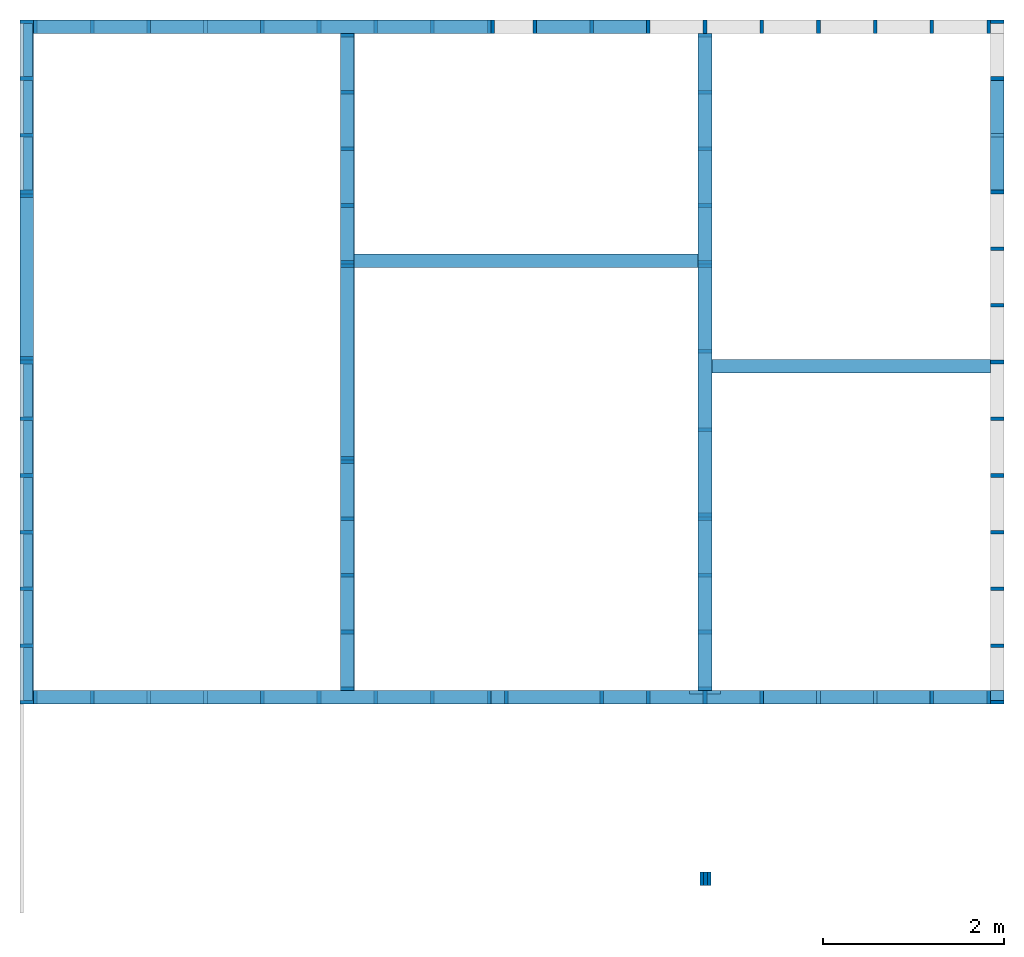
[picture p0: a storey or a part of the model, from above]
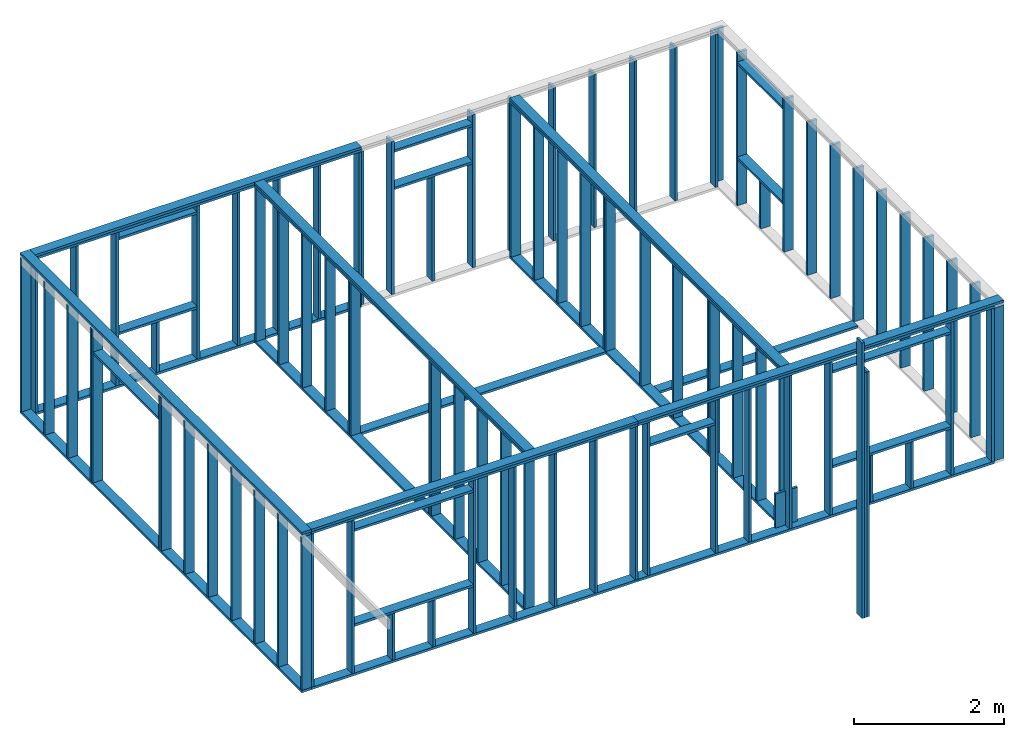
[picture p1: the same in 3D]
Properties of the parts of a building model (IFC4)

# File
Description: ViewDefinition [Renga View]
File name: Прокт каркасного дома.ifc
Time: 2023-05-16T19:59:36
Author: Fujitsu
Written by: IfcPlusPlus
Made in: Renga 5.11.49403.0

# IfcBuildingStorey (5)
Name | Elevation (mm) | Reference
Базовый уровень | 0 | Базовый уровень
Фасады | 0 | Фасады
Ниже 0.00 | 0 | Ниже 0.00
Кровля | 2620 | Кровля
Земля | -700 | Земля

# IfcBeam: Брус 40х40 (6)
In: Кровля
Type - PredefinedType: BEAM
Material: Древесина зел
Qto_BeamBaseQuantities - CrossSectionArea: 0.0016 m2
Name | Roll (deg) | Length (mm) | NetVolume (m3) | NetWeight (kg) | OuterSurfaceArea (m2)
4 x Балка - Брус 40х40 | 72.4 | 1500 | 0.00216 | 1.296 | 0.224
2 x Балка - Брус 40х40 | 0 | 4500 | 0.0072 | 4.32 | 0.72

# IfcBeam: Доска 25х100 (12)
In: Фасады
Type - PredefinedType: BEAM
Material: Древесина белая крашенная
Qto_BeamBaseQuantities - CrossSectionArea: 0.0025 m2
Name | Roll (deg) | Length (mm) | NetVolume (m3) | NetWeight (kg) | OuterSurfaceArea (m2)
Балка - Доска 25х100 | 0 | 2980.77 | 0.00730193 | 4.38116 | 0.742693
Балка - Доска 25х100 | 90 | 1841.45 | 0.00460362 | 2.76217 | 0.460362
Балка - Доска 25х100 | 90 | 2783.76 | 0.00695941 | 4.17565 | 0.695941
Балка - Доска 25х100 | 0 | 2980.77 | 0.00735818 | 4.41491 | 0.738943
4 x Балка - Доска 25х100 | 0 | 1700 | 0.00425 | 2.55 | 0.425
4 x Балка - Доска 25х100 | 90 | 1800 | 0.0045 | 2.7 | 0.45

# IfcBeam: Доска 25х150 (2)
In: Кровля
Type - PredefinedType: BEAM
Material: Древесина зел
Qto_BeamBaseQuantities - CrossSectionArea: 0.00375 m2; Length: 1500 mm; NetVolume: 0.005625 m3; NetWeight: 3.375 kg; OuterSurfaceArea: 0.525 m2
Name | Roll (deg)
Балка - Доска 25х150 | 162.5
Балка - Доска 25х150 | 13.11

# IfcBeam: Доска 40х100, Балка - Доска 40х100
In: Базовый уровень
Type - PredefinedType: BEAM
Material: Древесина конструктивная
Pset_BeamCommon - Roll: 0 deg
Qto_BeamBaseQuantities - CrossSectionArea: 0.004 m2; Length: 7540 mm; NetVolume: 0.03016 m3; NetWeight: 18.096 kg; OuterSurfaceArea: 2.1112 m2

# IfcBeam: Доска 40х150 (111)
Type - PredefinedType: BEAM
Qto_BeamBaseQuantities - CrossSectionArea: 0.006 m2
Name | In | Material | Roll (deg) | Length (mm) | NetVolume (m3) | NetWeight (kg) | OuterSurfaceArea (m2)
4 x Балка - Доска 40х150 | Базовый уровень | Древесина конструктивная | 0 | 5505 | 0.03303 | 19.818 | 2.0919
4 x Балка - Доска 40х150 | Базовый уровень | Древесина конструктивная | 0 | 7540 | 0.04524 | 27.144 | 2.8652
7 x Балка - Доска 40х150 | Базовый уровень | Древесина конструктивная | 0 | 7240 | 0.04344 | 26.064 | 2.7512
2 x Балка - Доска 40х150 | Базовый уровень | Древесина конструктивная | 0 | 553.898 | 0.00332339 | 1.99403 | 0.210481
4 x Балка - Доска 40х150 | Базовый уровень | Древесина конструктивная | 0 | 1835 | 0.01101 | 6.606 | 0.6973
Балка - Доска 40х150 | Базовый уровень | Древесина конструктивная | 0 | 1010 | 0.00606 | 3.636 | 0.3838
6 x Балка - Доска 40х150 | Базовый уровень | Древесина конструктивная | 0 | 5040 | 0.03024 | 18.144 | 1.9152
6 x Балка - Доска 40х150 | Базовый уровень | Древесина конструктивная | 0 | 1210 | 0.00726 | 4.356 | 0.4598
Балка - Доска 40х150 | Базовый уровень | Древесина конструктивная | 0 | 1755 | 0.01053 | 6.318 | 0.6669
Балка - Доска 40х150 | Базовый уровень | Древесина конструктивная | 0 | 3070 | 0.01842 | 11.052 | 1.1666
Балка - Доска 40х150 | Базовый уровень | Древесина конструктивная | 0 | 3792.5 | 0.022755 | 13.653 | 1.44115
2 x Балка - Доска 40х150 | Базовый уровень | Древесина конструктивная | 0 | 5655 | 0.03393 | 20.358 | 2.1489
Балка - Доска 40х150 | Кровля | Древесина жел | 90 | 9840 | 0.05874 | 35.244 | 3.7202
Балка - Доска 40х150 | Кровля | Древесина жел | 90 | 7500 | 0.045 | 27 | 2.85
Балка - Доска 40х150 | Кровля | Древесина жел | 90 | 7272.5 | 0.043635 | 26.181 | 2.76355
Балка - Доска 40х150 | Кровля | Древесина жел | 90 | 7232.5 | 0.043395 | 26.037 | 2.74835
11 x Балка - Доска 40х150 | Кровля | Древесина жел | 90 | 3500 | 0.021 | 12.6 | 1.33
Балка - Доска 40х150 | Кровля | Древесина конструктивная | 0 | 7240 | 0.0433634 | 26.0181 | 2.7032
5 x Балка - Доска 40х150 | Кровля | Древесина жел | 90 | 585 | 0.00351 | 2.106 | 0.2223
2 x Балка - Доска 40х150 | Кровля | Древесина конструктивная | 0 | 7240 | 0.04344 | 26.064 | 2.7512
Балка - Доска 40х150 | Кровля | Древесина жел | 90 | 10230 | 0.0612926 | 36.7755 | 3.86916
Балка - Доска 40х150 | Кровля | Древесина жел | 90 | 10230 | 0.06048 | 36.288 | 3.8304
Балка - Доска 40х150 | Кровля | Древесина жел | 90 | 10180 | 0.0591527 | 35.4916 | 3.75443
Балка - Доска 40х150 | Кровля | Древесина конструктивная | 0 | 7312.5 | 0.0438559 | 26.3135 | 2.76649
3 x Балка - Доска 40х150 | Кровля | Древесина жел | 90 | 625 | 0.00375 | 2.25 | 0.2375
11 x Балка - Доска 40х150 | Кровля | Древесина жел | 90 | 4000 | 0.024 | 14.4 | 1.52
6 x Балка - Доска 40х150 | Кровля | Древесина жел | 90 | 545 | 0.00327 | 1.962 | 0.2071
Балка - Доска 40х150 | Кровля | Древесина конструктивная | 0 | 7312.5 | 0.043875 | 26.325 | 2.77875
Балка - Доска 40х150 | Кровля | Древесина жел | 90 | 545 | 0.00321382 | 1.92829 | 0.209542
Балка - Доска 40х150 | Кровля | Древесина жел | 90 | 2398.28 | 0.0143896 | 8.63379 | 0.911356
Балка - Доска 40х150 | Кровля | Древесина жел | 90 | 2205.12 | 0.0132307 | 7.93841 | 0.837956
11 x Балка - Доска 40х150 | Кровля | Древесина жел | 90 | 590 | 0.00354 | 2.124 | 0.2242
Балка - Доска 40х150 | Кровля | Древесина жел | 90 | 300 | 0.0018 | 1.08 | 0.114
Балка - Доска 40х150 | Кровля | Древесина конструктивная | 0 | 3739.95 | 0.0223713 | 13.4228 | 1.40903
Балка - Доска 40х150 | Кровля | Древесина жел | 90 | 2674.37 | 0.0156618 | 9.39709 | 1.01034
Балка - Доска 40х150 | Кровля | Древесина жел | 90 | 2832.29 | 0.0165864 | 9.95185 | 1.06406
Балка - Доска 40х150 | Базовый уровень | Древесина жел | 90 | 9840 | 0.056752 | 34.0512 | 3.604
Балка - Доска 40х150 | Кровля | Древесина конструктивная | 0 | 3698.88 | 0.0221805 | 13.3083 | 1.39476
Балка - Доска 40х150 | Кровля | Древесина жел | 90 | 4135 | 0.0241606 | 14.4964 | 1.54822
Балка - Доска 40х150 | Кровля | Древесина жел | 90 | 9840 | 0.0571505 | 34.2903 | 3.74252
Балка - Доска 40х150 | Кровля | Древесина жел | 90 | 4601.82 | 0.0270536 | 16.2321 | 1.71942
Балка - Доска 40х150 | Кровля | Древесина жел | 90 | 9596.1 | 0.0575692 | 34.5415 | 3.64562

# IfcBeam: Доска 50х200 (164)
Type - PredefinedType: BEAM
Pset_BeamCommon - Roll: 90 deg
Qto_BeamBaseQuantities - CrossSectionArea: 0.01 m2
Name | In | Material | Length (mm) | NetVolume (m3) | NetWeight (kg) | OuterSurfaceArea (m2)
8 x Балка - Доска 50х200 | Кровля | Древесина оранж | 5278.68 | 0.0527277 | 31.6366 | 2.63983
2 x Балка - Доска 50х200 | Ниже 0.00 | Древесина светлая | 3532.5 | 0.035325 | 21.195 | 1.76625
Балка - Доска 50х200 | Ниже 0.00 | Древесина светлая | 9465 | 0.09465 | 56.79 | 4.7325
Балка - Доска 50х200 | Ниже 0.00 | Древесина светлая | 10795 | 0.10795 | 64.77 | 5.3975
3 x Балка - Доска 50х200 | Ниже 0.00 | Древесина светлая | 9415 | 0.09415 | 56.49 | 4.7075
Балка - Доска 50х200 | Ниже 0.00 | Древесина светлая | 3482.5 | 0.034825 | 20.895 | 1.74125
3 x Балка - Доска 50х200 | Ниже 0.00 | Древесина светлая | 3892.5 | 0.038925 | 23.355 | 1.94625
2 x Балка - Доска 50х200 | Ниже 0.00 | Древесина светлая | 3220 | 0.0322 | 19.32 | 1.61
Балка - Доска 50х200 | Ниже 0.00 | Древесина светлая | 3170 | 0.0317 | 19.02 | 1.585
2 x Балка - Доска 50х200 | Ниже 0.00 | Древесина светлая | 7390 | 0.0739 | 44.34 | 3.695
4 x Балка - Доска 50х200 | Ниже 0.00 | Древесина светлая | 7340 | 0.0734 | 44.04 | 3.67
Балка - Доска 50х200 | Ниже 0.00 | Древесина светлая | 3120 | 0.0312 | 18.72 | 1.56
2 x Балка - Доска 50х200 | Ниже 0.00 | Древесина светлая | 3792.5 | 0.037925 | 22.755 | 1.89625
Балка - Доска 50х200 | Ниже 0.00 | Древесина светлая | 3432.5 | 0.034325 | 20.595 | 1.71625
Балка - Доска 50х200 | Ниже 0.00 | Древесина светлая | 3070 | 0.0307 | 18.42 | 1.535
Балка - Доска 50х200 | Ниже 0.00 | Древесина светлая | 3382.5 | 0.033825 | 20.295 | 1.69125
2 x Балка - Доска 50х200 | Ниже 0.00 | Древесина светлая | 7290 | 0.0729 | 43.74 | 3.645
Балка - Доска 50х200 | Ниже 0.00 | Древесина зел | 10845 | 0.10845 | 65.07 | 5.4225
Балка - Доска 50х200 | Ниже 0.00 | Древесина зел | 7490 | 0.0749 | 44.94 | 3.745
Балка - Доска 50х200 | Ниже 0.00 | Древесина зел | 10795 | 0.10795 | 64.77 | 5.3975
Балка - Доска 50х200 | Ниже 0.00 | Древесина зел | 7440 | 0.0744 | 44.64 | 3.72
7 x Балка - Доска 50х200 | Ниже 0.00 | Древесина зел | 405 | 0.00405 | 2.43 | 0.2025
14 x Балка - Доска 50х200 | Ниже 0.00 | Древесина зел | 3500 | 0.035 | 21 | 1.75
14 x Балка - Доска 50х200 | Ниже 0.00 | Древесина зел | 4500 | 0.045 | 27 | 2.25
14 x Балка - Доска 50х200 | Ниже 0.00 | Древесина зел | 4000 | 0.04 | 24 | 2
11 x Балка - Доска 50х200 | Ниже 0.00 | Древесина зел | 355 | 0.00355 | 2.13 | 0.1775
26 x Балка - Доска 50х200 | Ниже 0.00 | Древесина зел | 410 | 0.0041 | 2.46 | 0.205
11 x Балка - Доска 50х200 | Кровля | Древесина оранж | 5500 | 0.0547918 | 32.8751 | 2.74526
12 x Балка - Доска 50х200 | Кровля | Древесина оранж | 5500 | 0.0546228 | 32.7737 | 2.74056
Балка - Доска 50х200 | Кровля | Древесина оранж | 5278.68 | 0.0527269 | 31.6362 | 2.63979
Балка - Доска 50х200 | Кровля | Древесина оранж | 5278.68 | 0.0527253 | 31.6352 | 2.63983
Балка - Доска 50х200 | Кровля | Древесина оранж | 5278.68 | 0.0527269 | 31.6362 | 2.63978
Балка - Доска 50х200 | Кровля | Древесина оранж | 5278.68 | 0.0527253 | 31.6352 | 2.63984
Балка - Доска 50х200 | Кровля | Древесина оранж | 5500 | 0.0547825 | 32.8695 | 2.74284
Балка - Доска 50х200 | Кровля | Древесина белая крашенная | 4154.23 | 0.0414668 | 24.8801 | 2.07768
Балка - Доска 50х200 | Кровля | Древесина белая крашенная | 3500 | 0.035 | 21 | 1.75
Балка - Доска 50х200 | Кровля | Древесина белая крашенная | 5500 | 0.0549907 | 32.9944 | 2.75004
2 x Балка - Доска 50х200 | Кровля | Древесина оранж | 4154.23 | 0.0414668 | 24.8801 | 2.07768
2 x Балка - Доска 50х200 | Кровля | Древесина оранж | 5500 | 0.0549814 | 32.9888 | 2.75008
2 x Балка - Доска 50х200 | Кровля | Древесина оранж | 5500 | 0.0549907 | 32.9944 | 2.75004
Балка - Доска 50х200 | Кровля | Древесина оранж | 5145.79 | 0.0508826 | 30.5296 | 2.56087

# IfcColumn: 100-100, Колонна - 100-100
In: Фасады
Type - PredefinedType: COLUMN
Pset_ColumnCommon - Roll: 0 deg
Pset_ReinforcementBarPitchOfColumn - ReinforcementBarType: (нет)
Qto_ColumnBaseQuantities - CrossSectionArea: 0.01 m2; Length: 3000 mm; NetVolume: 0.03 m3; OuterSurfaceArea: 1.2 m2

# IfcColumn: Доска 40x150 (127)
Type - PredefinedType: COLUMN
Pset_ReinforcementBarPitchOfColumn - ReinforcementBarType: (нет)
Qto_ColumnBaseQuantities - CrossSectionArea: 0.006 m2
Name | In | Material | Roll (deg) | Length (mm) | NetVolume (m3) | NetWeight (kg) | OuterSurfaceArea (m2)
50 x Колонна - Доска 40x150 | Базовый уровень | Древесина тёмная | 0 | 2500 | 0.015 | 9 | 0.95
31 x Колонна - Доска 40x150 | Базовый уровень | Древесина тёмная | 90 | 2500 | 0.015 | 9 | 0.95
Колонна - Доска 40x150 | Базовый уровень | Древесина тёмная | 0 | 760 | 0.00456 | 2.736 | 0.2888
Колонна - Доска 40x150 | Базовый уровень | Древесина тёмная | 90 | 1700 | 0.0102 | 6.12 | 0.646
Колонна - Доска 40x150 | Базовый уровень | Древесина тёмная | 90 | 820 | 0.00492 | 2.952 | 0.3116
4 x Колонна - Доска 40x150 | Базовый уровень | Древесина тёмная | 90 | 760 | 0.00456 | 2.736 | 0.2888
11 x Колонна - Доска 40x150 | Кровля | Древесина тёмная | 0 | 587 | 0.003522 | 2.1132 | 0.22306
Колонна - Доска 40x150 | Кровля | Древесина тёмная | 90 | 1375 | 0.00825 | 4.95 | 0.5225
9 x Колонна - Доска 40x150 | Кровля | Древесина тёмная | 90 | 1525 | 0.00915 | 5.49 | 0.5795
2 x Колонна - Доска 40x150 | Кровля | Древесина тёмная | 90 | 774 | 0.004644 | 2.7864 | 0.29412
2 x Колонна - Доска 40x150 | Кровля | Древесина тёмная | 90 | 142 | 0.000852 | 0.5112 | 0.05396
2 x Колонна - Доска 40x150 | Кровля | Древесина тёмная | 90 | 280 | 0.00168 | 1.008 | 0.1064
2 x Колонна - Доска 40x150 | Кровля | Древесина тёмная | 90 | 432 | 0.002592 | 1.5552 | 0.16416
2 x Колонна - Доска 40x150 | Кровля | Древесина тёмная | 90 | 570 | 0.00342 | 2.052 | 0.2166
2 x Колонна - Доска 40x150 | Кровля | Древесина тёмная | 90 | 708 | 0.004248 | 2.5488 | 0.26904
2 x Колонна - Доска 40x150 | Кровля | Древесина тёмная | 90 | 862 | 0.005172 | 3.1032 | 0.32756
2 x Колонна - Доска 40x150 | Базовый уровень | Древесина белая крашенная | 90 | 4000 | 0.024 | 14.4 | 1.52
Колонна - Доска 40x150 | Базовый уровень | Древесина белая крашенная | 90 | 4500 | 0.027 | 16.2 | 1.71
Колонна - Доска 40x150 | Кровля | Древесина тёмная | 0 | 1100 | 0.0066 | 3.96 | 0.418

# IfcColumn: Круглая (усл) 107 (20)
In: Ниже 0.00
Type - PredefinedType: COLUMN
Material: Сталь
Pset_ColumnCommon - Roll: 0 deg
Pset_ReinforcementBarPitchOfColumn - ReinforcementBarType: (нет)
Qto_ColumnBaseQuantities - CrossSectionArea: 0.011449 m2; Length: 250 mm; NetVolume: 0.00286225 m3; NetWeight: 22.3255 kg; OuterSurfaceArea: 0.107 m2

# IfcSlab (56)
PredefinedType: FLOOR
Pset_ReinforcementBarPitchOfSlab - Description: (нет)
Name (Перекрытие:...) | In | NetArea (m2) | NetVolume (m3) | Perimeter (mm) | Width (mm) | Material | NetWeight (kg)
 200,00 мм | Фасады | 21.7689 | 4.35377 | 25790 | 200
17 x  21,00 мм | Ниже 0.00 | 2.09687 | 0.0440344 | 6100 | 21 | фанера) | 26.4206
9 x  21,00 мм | Ниже 0.00 | 2.32563 | 0.0488381 | 6100 | 21 | фанера) | 29.3029
 21,00 мм | Ниже 0.00 | 1.89512 | 0.0397976 | 6100 | 21 | фанера) | 23.8786
 21,00 мм | Ниже 0.00 | 2.09537 | 0.0440029 | 6100 | 21 | фанера) | 26.4017
 21,00 мм | Ниже 0.00 | 1.89213 | 0.0397346 | 6100 | 21 | фанера) | 23.8408
2 x  21,00 мм | Ниже 0.00 | 1.90187 | 0.0399394 | 6100 | 21 | фанера) | 23.9636
 21,00 мм | Ниже 0.00 | 1.89513 | 0.0397976 | 6100 | 21 | фанера) | 23.8786
 21,00 мм | Ниже 0.00 | 1.963 | 0.041223 | 6100 | 21 | фанера) | 24.7338
 21,00 мм | Ниже 0.00 | 1.89663 | 0.0398291 | 6100 | 21 | фанера) | 23.8975
 21,00 мм | Ниже 0.00 | 1.69091 | 0.0355091 | 5202.77 | 21 | фанера) | 21.3055
20 x  5,00 мм | Ниже 0.00 | 0.04 | 0.0002 | 800 | 5 | Сталь | 1.56

# IfcStairFlight, Лестница: 3 шт x 300,00 мм x 233,33 мм
In: Фасады
Pset_StairFlightCommon - NumberOfRiser: 3; NumberOfTreads: 3; RiserHeight: 233.333 mm
Qto_StairFlightBaseQuantities - NetVolume: 0.155 m3

# Material: Древесина тёмная
Pset_MaterialCommon - MassDensity: 600 kg/m3
Pset_MaterialThermal - ThermalConductivity: 0.12

# Material: Древесина белая крашенная
Pset_MaterialCommon - MassDensity: 600 kg/m3
Pset_MaterialThermal - ThermalConductivity: 0.12

# Material: фанера)
Pset_MaterialCommon - MassDensity: 600 kg/m3
Pset_MaterialThermal - ThermalConductivity: 0.12

# Material: Древесина конструктивная
Pset_MaterialCommon - MassDensity: 600 kg/m3
Pset_MaterialThermal - ThermalConductivity: 0.12

# Material: Древесина жел
Pset_MaterialCommon - MassDensity: 600 kg/m3
Pset_MaterialThermal - ThermalConductivity: 0.12

# Material: Древесина оранж
Pset_MaterialCommon - MassDensity: 600 kg/m3
Pset_MaterialThermal - ThermalConductivity: 0.12

# Material: Древесина светлая
Pset_MaterialCommon - MassDensity: 600 kg/m3
Pset_MaterialThermal - ThermalConductivity: 0.12

# Material: Древесина зел
Pset_MaterialCommon - MassDensity: 600 kg/m3
Pset_MaterialThermal - ThermalConductivity: 0.12

# Material: Сталь
Pset_MaterialCommon - MassDensity: 7800 kg/m3
Pset_MaterialThermal - ThermalConductivity: 50
